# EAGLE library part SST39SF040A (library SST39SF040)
4 Mbit x8 Multi-Purpose Flash Source: http://www.sst.com/dotAsset/40782.pdf

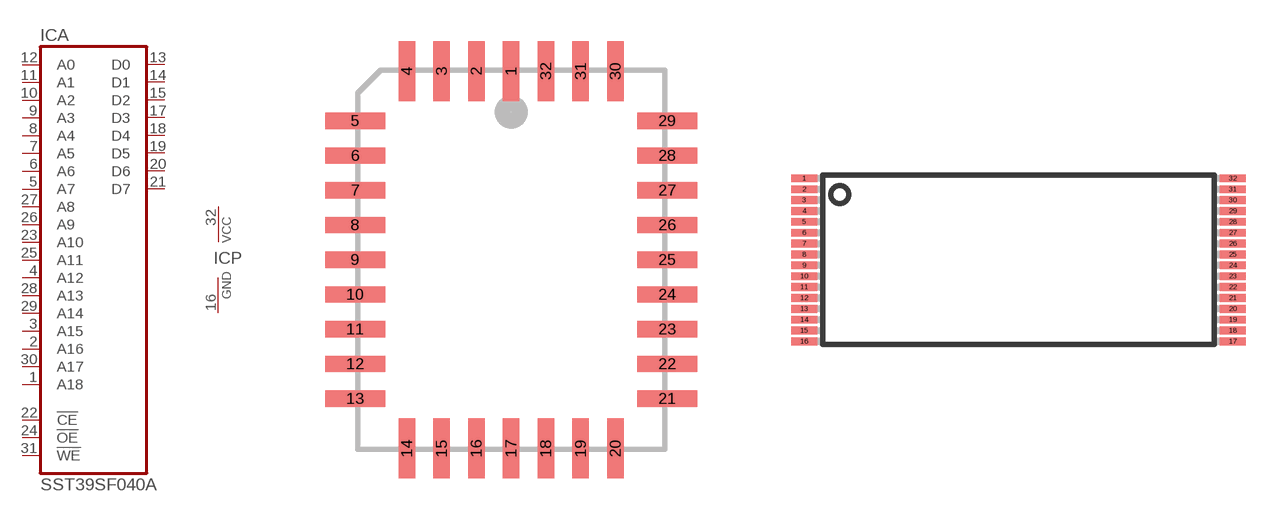
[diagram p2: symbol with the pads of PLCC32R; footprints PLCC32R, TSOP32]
Designator prefix IC; gates A=SST39SF040 P=PWRN

## SST39SF040AN  [PLCC32R]
1  A:A18  in
2  A:A16  in
3  A:A15  in
4  A:A12  in
5  A:A7  in
6  A:A6  in
7  A:A5  in
8  A:A4  in
9  A:A3  in
10  A:A2  in
11  A:A1  in
12  A:A0  in
13  A:D0
14  A:D1
15  A:D2
16  P:GND  pwr
17  A:D3
18  A:D4
19  A:D5
20  A:D6
21  A:D7
22  A:!CE  in
23  A:A10  in
24  A:!OE  in
25  A:A11  in
26  A:A9  in
27  A:A8  in
28  A:A13  in
29  A:A14  in
30  A:A17  in
31  A:!WE  in
32  P:VCC  pwr

## SST39SF040AW  [TSOP32]
1  A:A11  in
2  A:A9  in
3  A:A8  in
4  A:A13  in
5  A:A14  in
6  A:A17  in
7  A:!WE  in
8  P:VCC  pwr
9  A:A18  in
10  A:A16  in
11  A:A15  in
12  A:A12  in
13  A:A7  in
14  A:A6  in
15  A:A5  in
16  A:A4  in
17  A:A3  in
18  A:A2  in
19  A:A1  in
20  A:A0  in
21  A:D0
22  A:D1
23  A:D2
24  P:GND  pwr
25  A:D3
26  A:D4
27  A:D5
28  A:D6
29  A:D7
30  A:!CE  in
31  A:A10  in
32  A:!OE  in

## SST39SF040APH  [DIL32]
Pads as for PLCC32R

## SST39SF040APHR  [DIL32-RP]
Pads as for PLCC32R

## SST39SF040APHS  [DIL32-SMD]
Pads as for PLCC32R

## Footprint PLCC32R (pad centres in mm)
PLASTIC LEADED CHIP CARRIER rectangle
smd 0.6 x 2.2: 1 0,6.9; 2 -1.27,6.9; 3 -2.54,6.9; 4 -3.81,6.9; 14 -3.81,-6.9; 15 -2.54,-6.9; 16 -1.27,-6.9; 17 0,-6.9; 18 1.27,-6.9; 19 2.54,-6.9; 20 3.81,-6.9; 30 3.81,6.9; 31 2.54,6.9; 32 1.27,6.9
smd 2.2 x 0.6: 5 -5.7,5.08; 6 -5.7,3.81; 7 -5.7,2.54; 8 -5.7,1.27; 9 -5.7,0; 10 -5.7,-1.27; 11 -5.7,-2.54; 12 -5.7,-3.81; 13 -5.7,-5.08; 21 5.7,-5.08; 22 5.7,-3.81; 23 5.7,-2.54; 24 5.7,-1.27; 25 5.7,0; 26 5.7,1.27; 27 5.7,2.54; 28 5.7,3.81; 29 5.7,5.08

## Footprint TSOP32 (pad centres in mm)
Thin Small Outline Package
smd 1.2 x 0.36: 1 -9.85,3.75; 2 -9.85,3.25; 3 -9.85,2.75; 4 -9.85,2.25; 5 -9.85,1.75; 6 -9.85,1.25; 7 -9.85,0.75; 8 -9.85,0.25; 9 -9.85,-0.25; 10 -9.85,-0.75; 11 -9.85,-1.25; 12 -9.85,-1.75; 13 -9.85,-2.25; 14 -9.85,-2.75; 15 -9.85,-3.25; 16 -9.85,-3.75; 17 9.85,-3.75; 18 9.85,-3.25; 19 9.85,-2.75; 20 9.85,-2.25; 21 9.85,-1.75; 22 9.85,-1.25; 23 9.85,-0.75; 24 9.85,-0.25; 25 9.85,0.25; 26 9.85,0.75; 27 9.85,1.25; 28 9.85,1.75; 29 9.85,2.25; 30 9.85,2.75; 31 9.85,3.25; 32 9.85,3.75

## Footprint DIL32 (pad centres in mm)
Dual In Line Package
drill 0.813 long: 1 -19.05,-7.62; 2 -16.51,-7.62; 3 -13.97,-7.62; 4 -11.43,-7.62; 5 -8.89,-7.62; 6 -6.35,-7.62; 7 -3.81,-7.62; 8 -1.27,-7.62; 9 1.27,-7.62; 10 3.81,-7.62; 11 6.35,-7.62; 12 8.89,-7.62; 13 11.43,-7.62; 14 13.97,-7.62; 15 16.51,-7.62; 16 19.05,-7.62; 17 19.05,7.62; 18 16.51,7.62; 19 13.97,7.62; 20 11.43,7.62; 21 8.89,7.62; 22 6.35,7.62; 23 3.81,7.62; 24 1.27,7.62; 25 -1.27,7.62; 26 -3.81,7.62; 27 -6.35,7.62; 28 -8.89,7.62; 29 -11.43,7.62; 30 -13.97,7.62; 31 -16.51,7.62; 32 -19.05,7.62

## Footprint DIL32-RP (pad centres in mm)
Dual In Line Package
drill 0.813 square: 1 -19.05,-7.62
drill 0.813: 2 -16.51,-7.62; 3 -13.97,-7.62; 4 -11.43,-7.62; 5 -8.89,-7.62; 6 -6.35,-7.62; 7 -3.81,-7.62; 8 -1.27,-7.62; 9 1.27,-7.62; 10 3.81,-7.62; 11 6.35,-7.62; 12 8.89,-7.62; 13 11.43,-7.62; 14 13.97,-7.62; 15 16.51,-7.62; 16 19.05,-7.62; 17 19.05,7.62; 18 16.51,7.62; 19 13.97,7.62; 20 11.43,7.62; 21 8.89,7.62; 22 6.35,7.62; 23 3.81,7.62; 24 1.27,7.62; 25 -1.27,7.62; 26 -3.81,7.62; 27 -6.35,7.62; 28 -8.89,7.62; 29 -11.43,7.62; 30 -13.97,7.62; 31 -16.51,7.62; 32 -19.05,7.62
